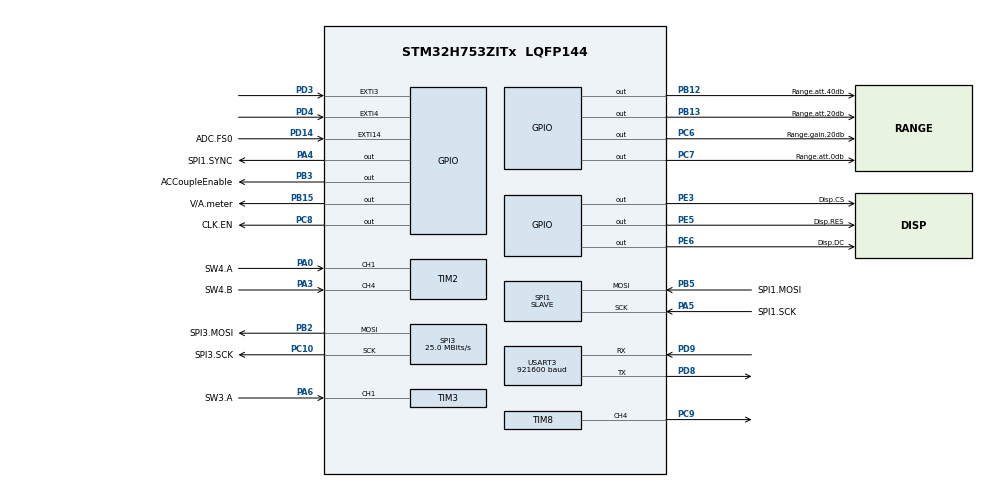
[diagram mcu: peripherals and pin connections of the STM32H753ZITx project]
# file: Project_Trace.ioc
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Dma.Request0=SPI1_RX
Dma.Request1=SPI3_TX
Dma.SPI1_RX.0.Direction=DMA_PERIPH_TO_MEMORY
Dma.SPI1_RX.0.EventEnable=DISABLE
Dma.SPI1_RX.0.FIFOMode=DMA_FIFOMODE_DISABLE
Dma.SPI1_RX.0.Instance=DMA1_Stream1
Dma.SPI1_RX.0.MemDataAlignment=DMA_MDATAALIGN_HALFWORD
Dma.SPI1_RX.0.MemInc=DMA_MINC_ENABLE
Dma.SPI1_RX.0.Mode=DMA_CIRCULAR
Dma.SPI1_RX.0.PeriphDataAlignment=DMA_PDATAALIGN_HALFWORD
Dma.SPI1_RX.0.PeriphInc=DMA_PINC_DISABLE
Dma.SPI1_RX.0.Polarity=HAL_DMAMUX_REQ_GEN_RISING
Dma.SPI1_RX.0.Priority=DMA_PRIORITY_LOW
Dma.SPI1_RX.0.RequestNumber=1
Dma.SPI1_RX.0.SignalID=NONE
Dma.SPI1_RX.0.SyncEnable=ENABLE
Dma.SPI1_RX.0.SyncPolarity=HAL_DMAMUX_SYNC_RISING
Dma.SPI1_RX.0.SyncRequestNumber=1
Dma.SPI1_RX.0.SyncSignalID=NONE
Dma.SPI3_TX.1.Direction=DMA_MEMORY_TO_PERIPH
Dma.SPI3_TX.1.EventEnable=DISABLE
Dma.SPI3_TX.1.FIFOMode=DMA_FIFOMODE_DISABLE
Dma.SPI3_TX.1.Instance=DMA1_Stream0
Dma.SPI3_TX.1.MemDataAlignment=DMA_MDATAALIGN_BYTE
Dma.SPI3_TX.1.MemInc=DMA_MINC_ENABLE
Dma.SPI3_TX.1.Mode=DMA_NORMAL
Dma.SPI3_TX.1.PeriphDataAlignment=DMA_PDATAALIGN_BYTE
Dma.SPI3_TX.1.PeriphInc=DMA_PINC_DISABLE
Dma.SPI3_TX.1.Polarity=HAL_DMAMUX_REQ_GEN_RISING
Dma.SPI3_TX.1.Priority=DMA_PRIORITY_LOW
Dma.SPI3_TX.1.RequestNumber=1
Dma.SPI3_TX.1.SignalID=NONE
Dma.SPI3_TX.1.SyncEnable=DISABLE
Dma.SPI3_TX.1.SyncPolarity=HAL_DMAMUX_SYNC_NO_EVENT
Dma.SPI3_TX.1.SyncRequestNumber=1
Dma.SPI3_TX.1.SyncSignalID=NONE
Mcu.Family=STM32H7
Mcu.Name=STM32H753ZITx
Mcu.Package=LQFP144
NVIC.DMA1_Stream0_IRQn=true\:0\:0\:false\:false\:true\:false\:true
NVIC.DMA1_Stream1_IRQn=true\:0\:0\:false\:false\:true\:false\:true
NVIC.DMAMUX1_OVR_IRQn=true\:0\:0\:false\:false\:true\:false\:true
NVIC.PriorityGroup=NVIC_PRIORITYGROUP_4
NVIC.SPI1_IRQn=true\:0\:0\:false\:false\:true\:false\:true
NVIC.SPI3_IRQn=true\:0\:0\:false\:false\:true\:false\:true
NVIC.TIM1_UP_IRQn=true\:0\:0\:true\:false\:true\:true\:true
NVIC.TIM8_UP_TIM13_IRQn=true\:0\:0\:false\:false\:true\:true\:true
PA0.GPIO_Label=SW4.A
PA0.Signal=S_TIM2_CH1_ETR
PA3.GPIO_Label=SW4.B
PA3.Signal=S_TIM2_CH4
PA4.GPIO_Label=SPI1.SYNC
PA4.GPIO_Speed=GPIO_SPEED_FREQ_HIGH
PA4.Signal=GPIO_Output
PA5.GPIO_Label=SPI1.SCK
PA5.Mode=RX_Only_Simplex_Unidirect_Slave
PA5.Signal=SPI1_SCK
PA6.GPIO_Label=SW3.A
PA6.Signal=S_TIM3_CH1
PB12.GPIO_Label=Range.att.40db
PB12.Signal=GPIO_Output
PB13.GPIO_Label=Range.att.20db
PB13.Signal=GPIO_Output
PB15.GPIO_Label=V/A.meter
PB15.Signal=GPIO_Output
PB2.GPIO_Label=SPI3.MOSI
PB2.Mode=TX_Only_Simplex_Unidirect_Master
PB2.Signal=SPI3_MOSI
PB3\ (JTDO/TRACESWO).GPIO_Label=ACCoupleEnable
PB3\ (JTDO/TRACESWO).Signal=GPIO_Output
PB5.GPIO_Label=SPI1.MOSI
PB5.Mode=RX_Only_Simplex_Unidirect_Slave
PB5.Signal=SPI1_MOSI
PC10.GPIO_Label=SPI3.SCK
PC10.Mode=TX_Only_Simplex_Unidirect_Master
PC10.Signal=SPI3_SCK
PC6.GPIO_Label=Range.gain.20db
PC6.Signal=GPIO_Output
PC7.GPIO_Label=Range.att.0db
PC7.Signal=GPIO_Output
PC8.GPIO_Label=CLK.EN
PC8.Signal=GPIO_Output
PC9.Signal=S_TIM8_CH4
PD14.GPIO_Label=ADC.FS0
PD14.GPIO_ModeDefaultEXTI=GPIO_MODE_IT_RISING
PD14.Signal=GPXTI14
PD3.Signal=GPXTI3
PD4.Signal=GPXTI4
PD8.Mode=Asynchronous
PD8.Signal=USART3_TX
PD9.Mode=Asynchronous
PD9.Signal=USART3_RX
PE3.GPIO_Label=Disp.CS
PE3.Signal=GPIO_Output
PE5.GPIO_Label=Disp.RES
PE5.Signal=GPIO_Output
PE6.GPIO_Label=Disp.DC
PE6.Signal=GPIO_Output
PH0-OSC_IN\ (PH0).Mode=HSE-External-Oscillator
PH0-OSC_IN\ (PH0).Signal=RCC_OSC_IN
PH1-OSC_OUT\ (PH1).Mode=HSE-External-Oscillator
PH1-OSC_OUT\ (PH1).Signal=RCC_OSC_OUT
ProjectManager.HeapSize=0x200
ProjectManager.StackSize=0x400
ProjectManager.TargetToolchain=STM32CubeIDE
RCC.ADCFreq_Value=129000000
RCC.APB1Freq_Value=50000000
RCC.APB2Freq_Value=100000000
RCC.APB3Freq_Value=100000000
RCC.APB4Freq_Value=100000000
RCC.CortexFreq_Value=200000000
RCC.D2PPRE1=RCC_APB1_DIV2
RCC.DIVM1=4
RCC.DIVN1=25
RCC.DIVQ1=4
RCC.HCLKFreq_Value=100000000
RCC.HPRE=RCC_HCLK_DIV2
RCC.PLLFRACN=0
RCC.SYSCLKFreq_VALUE=200000000
RCC.SYSCLKSource=RCC_SYSCLKSOURCE_PLLCLK
RCC.USBFreq_Value=100000000
SH.S_TIM2_CH1_ETR.0=TIM2_CH1,Input_Capture1_from_TI1
SH.S_TIM2_CH4.0=TIM2_CH4,Input_Capture4_from_TI4
SH.S_TIM3_CH1.0=TIM3_CH1,Input_Capture1_from_TI1
SH.S_TIM8_CH4.0=TIM8_CH4,PWM Generation4 CH4
SPI1.CLKPhase=SPI_PHASE_2EDGE
SPI1.CLKPolarity=SPI_POLARITY_LOW
SPI1.DataSize=SPI_DATASIZE_16BIT
SPI1.Direction=SPI_DIRECTION_2LINES_RXONLY
SPI1.Mode=SPI_MODE_SLAVE
SPI1.VirtualType=VM_SLAVE
SPI3.BaudRatePrescaler=SPI_BAUDRATEPRESCALER_4
SPI3.CalculateBaudRate=25.0 MBits/s
SPI3.DataSize=SPI_DATASIZE_8BIT
SPI3.Direction=SPI_DIRECTION_2LINES_TXONLY
SPI3.Mode=SPI_MODE_MASTER
SPI3.VirtualType=VM_MASTER
TIM1.Period=32768
TIM1.Prescaler=1000
TIM2.Channel-Input_Capture1_from_TI1=TIM_CHANNEL_1
TIM2.Channel-Input_Capture4_from_TI4=TIM_CHANNEL_4
TIM3.Channel-Input_Capture1_from_TI1=TIM_CHANNEL_1
TIM8.Channel-PWM\ Generation4\ CH4=TIM_CHANNEL_4
TIM8.OCFastMode_PWM-PWM\ Generation4\ CH4=TIM_OCFAST_ENABLE
TIM8.Period=3
TIM8.Prescaler=1
TIM8.Pulse-PWM\ Generation4\ CH4=2
USART3.BaudRate=921600
USART3.VirtualMode-Asynchronous=VM_ASYNC
VP_TIM1_VS_ClockSourceINT.Mode=Internal
VP_TIM8_VS_ClockSourceINT.Mode=Internal
board=custom

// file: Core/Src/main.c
/* USER CODE BEGIN Header */
/**
  ******************************************************************************
  * @file           : main.c
  * @brief          : Main program body
  ******************************************************************************
  * @attention
  *
  * Copyright (c) 2026 STMicroelectronics.
  * All rights reserved.
  *
  * This software is licensed under terms that can be found in the LICENSE file
  * in the root directory of this software component.
  * If no LICENSE file comes with this software, it is provided AS-IS.
  *
  ******************************************************************************
  */
/* USER CODE END Header */
#include "main.h"

/* USER CODE BEGIN Includes */
#include <stdio.h>
#include <stm32h7xx_hal.h>
#include <stdint.h>
#include <menu_system.h>
#include <graphics.h>

#include <adc.h>
#include <hal_oled.h>
#include <hal_signal_path.h>
#include <test_suite.h>
#include <sample_buffer.h>

#include <serialization.h>

#include <assert.h>

/* USER CODE END Includes */

/* USER CODE BEGIN PD */
//#define RUN_TESTS
/* USER CODE END PD */

SPI_HandleTypeDef hspi1;
SPI_HandleTypeDef hspi3;
DMA_HandleTypeDef hdma_spi1_rx;
DMA_HandleTypeDef hdma_spi3_tx;

TIM_HandleTypeDef htim1;
TIM_HandleTypeDef htim2;
TIM_HandleTypeDef htim3;
TIM_HandleTypeDef htim8;

UART_HandleTypeDef huart3;

void SystemClock_Config(void);
static void MX_GPIO_Init(void);
static void MX_DMA_Init(void);
static void MX_SPI3_Init(void);
static void MX_TIM2_Init(void);
static void MX_SPI1_Init(void);
static void MX_TIM3_Init(void);
static void MX_USART3_UART_Init(void);
static void MX_TIM8_Init(void);
static void MX_TIM1_Init(void);

/* USER CODE BEGIN 0 */
extern SampleBuffer sample_buffer;

int __io_putchar(int ch)
  {
   uint8_t c[1];
   c[0] = ch & 0x00FF;
   HAL_UART_Transmit(&huart3, &*c, 1, HAL_MAX_DELAY);
   return ch;
  }
/* USER CODE END 0 */

int main(void)
{

  /* MCU Configuration--------------------------------------------------------*/

  /* Reset of all peripherals, Initializes the Flash interface and the Systick. */
  HAL_Init();

  /* Configure the system clock */
  SystemClock_Config();

  /* Initialize all configured peripherals */
  MX_GPIO_Init();
  MX_DMA_Init();
  MX_SPI3_Init();
  MX_TIM2_Init();
  MX_SPI1_Init();
  MX_TIM3_Init();
  MX_USART3_UART_Init();
  MX_TIM8_Init();
  MX_TIM1_Init();
  /* USER CODE BEGIN 2 */
  //HAL_MspInit();
  //HAL_SPI_MspInit(&hspi1);

  printf("Hello, There!\r\n");
#ifdef RUN_TESTS
  printf("Running Tests!\r\n");

  //test_suite();
  while(1){}
#endif

  //__disable_irq();

  printf("Init Signal Path\n");
  hal_signal_path_init();
  hal_signal_path_attenuator_set(SignalPathAtten_0db);
  hal_signal_path_accouple_en(0);

  sample_buffer_init(&sample_buffer, 12500000); // TODO: use precise sample-rate
  printf("Init ADC\n");
  adc_init();

  printf("Init OLED\n");
  hal_oled_init();
  printf("Init Menu\n");
  menu_init();

  printf("Start ADC CLK\n");
  HAL_TIM_PWM_Start(&htim8, TIM_CHANNEL_4);

  //const char* header_labels[1] = { "x" };
  //(void)ser_file_write_csv_header(stdout, header_labels, 1);

  //__enable_irq();
  /* USER CODE END 2 */

  /* Infinite loop */
  /* USER CODE BEGIN WHILE */
  graphics_draw_rect_rel(5, 5, 10, 10);
  graphics_draw_text(8, 8, "address me");

  printf("Enter Loop\n");
  while (1)
  {
    /* USER CODE END WHILE */

    /* USER CODE BEGIN 3 */

//	  hal_oled_update_screen();
//	  for (uint32_t i = 0; i < 10000000LL; i++){}
//	  printf("Hi!\r\n");

  }
  /* USER CODE END 3 */
}

void SystemClock_Config(void)
{
  RCC_OscInitTypeDef RCC_OscInitStruct = {0};
  RCC_ClkInitTypeDef RCC_ClkInitStruct = {0};

  /** Supply configuration update enable
  */
  HAL_PWREx_ConfigSupply(PWR_LDO_SUPPLY);
  /** Configure the main internal regulator output voltage
  */
  __HAL_PWR_VOLTAGESCALING_CONFIG(PWR_REGULATOR_VOLTAGE_SCALE3);

  while(!__HAL_PWR_GET_FLAG(PWR_FLAG_VOSRDY)) {}
  /** Initializes the RCC Oscillators according to the specified parameters
  * in the RCC_OscInitTypeDef structure.
  */
  RCC_OscInitStruct.OscillatorType = RCC_OSCILLATORTYPE_HSI;
  RCC_OscInitStruct.HSIState = RCC_HSI_DIV1;
  RCC_OscInitStruct.HSICalibrationValue = RCC_HSICALIBRATION_DEFAULT;
  RCC_OscInitStruct.PLL.PLLState = RCC_PLL_ON;
  RCC_OscInitStruct.PLL.PLLSource = RCC_PLLSOURCE_HSI;
  RCC_OscInitStruct.PLL.PLLM = 4;
  RCC_OscInitStruct.PLL.PLLN = 25;
  RCC_OscInitStruct.PLL.PLLP = 2;
  RCC_OscInitStruct.PLL.PLLQ = 4;
  RCC_OscInitStruct.PLL.PLLR = 2;
  RCC_OscInitStruct.PLL.PLLRGE = RCC_PLL1VCIRANGE_3;
  RCC_OscInitStruct.PLL.PLLVCOSEL = RCC_PLL1VCOWIDE;
  RCC_OscInitStruct.PLL.PLLFRACN = 0;
  if (HAL_RCC_OscConfig(&RCC_OscInitStruct) != HAL_OK)
  {
    Error_Handler();
  }
  /** Initializes the CPU, AHB and APB buses clocks
  */
  RCC_ClkInitStruct.ClockType = RCC_CLOCKTYPE_HCLK|RCC_CLOCKTYPE_SYSCLK
                              |RCC_CLOCKTYPE_PCLK1|RCC_CLOCKTYPE_PCLK2
                              |RCC_CLOCKTYPE_D3PCLK1|RCC_CLOCKTYPE_D1PCLK1;
  RCC_ClkInitStruct.SYSCLKSource = RCC_SYSCLKSOURCE_PLLCLK;
  RCC_ClkInitStruct.SYSCLKDivider = RCC_SYSCLK_DIV1;
  RCC_ClkInitStruct.AHBCLKDivider = RCC_HCLK_DIV2;
  RCC_ClkInitStruct.APB3CLKDivider = RCC_APB3_DIV1;
  RCC_ClkInitStruct.APB1CLKDivider = RCC_APB1_DIV2;
  RCC_ClkInitStruct.APB2CLKDivider = RCC_APB2_DIV1;
  RCC_ClkInitStruct.APB4CLKDivider = RCC_APB4_DIV1;

  if (HAL_RCC_ClockConfig(&RCC_ClkInitStruct, FLASH_LATENCY_2) != HAL_OK)
  {
    Error_Handler();
  }
}

static void MX_SPI1_Init(void)
{

  /* SPI1 parameter configuration*/
  hspi1.Instance = SPI1;
  hspi1.Init.Mode = SPI_MODE_SLAVE;
  hspi1.Init.Direction = SPI_DIRECTION_2LINES_RXONLY;
  hspi1.Init.DataSize = SPI_DATASIZE_16BIT;
  hspi1.Init.CLKPolarity = SPI_POLARITY_LOW;
  hspi1.Init.CLKPhase = SPI_PHASE_2EDGE;
  hspi1.Init.NSS = SPI_NSS_SOFT;
  hspi1.Init.FirstBit = SPI_FIRSTBIT_MSB;
  hspi1.Init.TIMode = SPI_TIMODE_DISABLE;
  hspi1.Init.CRCCalculation = SPI_CRCCALCULATION_DISABLE;
  hspi1.Init.CRCPolynomial = 0x0;
  hspi1.Init.NSSPMode = SPI_NSS_PULSE_DISABLE;
  hspi1.Init.NSSPolarity = SPI_NSS_POLARITY_LOW;
  hspi1.Init.FifoThreshold = SPI_FIFO_THRESHOLD_01DATA;
  hspi1.Init.TxCRCInitializationPattern = SPI_CRC_INITIALIZATION_ALL_ZERO_PATTERN;
  hspi1.Init.RxCRCInitializationPattern = SPI_CRC_INITIALIZATION_ALL_ZERO_PATTERN;
  hspi1.Init.MasterSSIdleness = SPI_MASTER_SS_IDLENESS_00CYCLE;
  hspi1.Init.MasterInterDataIdleness = SPI_MASTER_INTERDATA_IDLENESS_00CYCLE;
  hspi1.Init.MasterReceiverAutoSusp = SPI_MASTER_RX_AUTOSUSP_DISABLE;
  hspi1.Init.MasterKeepIOState = SPI_MASTER_KEEP_IO_STATE_DISABLE;
  hspi1.Init.IOSwap = SPI_IO_SWAP_DISABLE;
  if (HAL_SPI_Init(&hspi1) != HAL_OK)
  {
    Error_Handler();
  }

}

static void MX_SPI3_Init(void)
{

  /* SPI3 parameter configuration*/
  hspi3.Instance = SPI3;
  hspi3.Init.Mode = SPI_MODE_MASTER;
  hspi3.Init.Direction = SPI_DIRECTION_2LINES_TXONLY;
  hspi3.Init.DataSize = SPI_DATASIZE_8BIT;
  hspi3.Init.CLKPolarity = SPI_POLARITY_LOW;
  hspi3.Init.CLKPhase = SPI_PHASE_1EDGE;
  hspi3.Init.NSS = SPI_NSS_SOFT;
  hspi3.Init.BaudRatePrescaler = SPI_BAUDRATEPRESCALER_4;
  hspi3.Init.FirstBit = SPI_FIRSTBIT_MSB;
  hspi3.Init.TIMode = SPI_TIMODE_DISABLE;
  hspi3.Init.CRCCalculation = SPI_CRCCALCULATION_DISABLE;
  hspi3.Init.CRCPolynomial = 0x0;
  hspi3.Init.NSSPMode = SPI_NSS_PULSE_ENABLE;
  hspi3.Init.NSSPolarity = SPI_NSS_POLARITY_LOW;
  hspi3.Init.FifoThreshold = SPI_FIFO_THRESHOLD_01DATA;
  hspi3.Init.TxCRCInitializationPattern = SPI_CRC_INITIALIZATION_ALL_ZERO_PATTERN;
  hspi3.Init.RxCRCInitializationPattern = SPI_CRC_INITIALIZATION_ALL_ZERO_PATTERN;
  hspi3.Init.MasterSSIdleness = SPI_MASTER_SS_IDLENESS_00CYCLE;
  hspi3.Init.MasterInterDataIdleness = SPI_MASTER_INTERDATA_IDLENESS_00CYCLE;
  hspi3.Init.MasterReceiverAutoSusp = SPI_MASTER_RX_AUTOSUSP_DISABLE;
  hspi3.Init.MasterKeepIOState = SPI_MASTER_KEEP_IO_STATE_DISABLE;
  hspi3.Init.IOSwap = SPI_IO_SWAP_DISABLE;
  if (HAL_SPI_Init(&hspi3) != HAL_OK)
  {
    Error_Handler();
  }

}

static void MX_TIM1_Init(void)
{

  TIM_ClockConfigTypeDef sClockSourceConfig = {0};
  TIM_MasterConfigTypeDef sMasterConfig = {0};

  htim1.Instance = TIM1;
  htim1.Init.Prescaler = 1000;
  htim1.Init.CounterMode = TIM_COUNTERMODE_UP;
  htim1.Init.Period = 32768;
  htim1.Init.ClockDivision = TIM_CLOCKDIVISION_DIV1;
  htim1.Init.RepetitionCounter = 0;
  htim1.Init.AutoReloadPreload = TIM_AUTORELOAD_PRELOAD_DISABLE;
  if (HAL_TIM_Base_Init(&htim1) != HAL_OK)
  {
    Error_Handler();
  }
  sClockSourceConfig.ClockSource = TIM_CLOCKSOURCE_INTERNAL;
  if (HAL_TIM_ConfigClockSource(&htim1, &sClockSourceConfig) != HAL_OK)
  {
    Error_Handler();
  }
  sMasterConfig.MasterOutputTrigger = TIM_TRGO_RESET;
  sMasterConfig.MasterOutputTrigger2 = TIM_TRGO2_RESET;
  sMasterConfig.MasterSlaveMode = TIM_MASTERSLAVEMODE_DISABLE;
  if (HAL_TIMEx_MasterConfigSynchronization(&htim1, &sMasterConfig) != HAL_OK)
  {
    Error_Handler();
  }

}

static void MX_TIM2_Init(void)
{

  TIM_MasterConfigTypeDef sMasterConfig = {0};
  TIM_IC_InitTypeDef sConfigIC = {0};

  htim2.Instance = TIM2;
  htim2.Init.Prescaler = 0;
  htim2.Init.CounterMode = TIM_COUNTERMODE_UP;
  htim2.Init.Period = 4294967295;
  htim2.Init.ClockDivision = TIM_CLOCKDIVISION_DIV1;
  htim2.Init.AutoReloadPreload = TIM_AUTORELOAD_PRELOAD_DISABLE;
  if (HAL_TIM_IC_Init(&htim2) != HAL_OK)
  {
    Error_Handler();
  }
  sMasterConfig.MasterOutputTrigger = TIM_TRGO_RESET;
  sMasterConfig.MasterSlaveMode = TIM_MASTERSLAVEMODE_DISABLE;
  if (HAL_TIMEx_MasterConfigSynchronization(&htim2, &sMasterConfig) != HAL_OK)
  {
    Error_Handler();
  }
  sConfigIC.ICPolarity = TIM_INPUTCHANNELPOLARITY_RISING;
  sConfigIC.ICSelection = TIM_ICSELECTION_DIRECTTI;
  sConfigIC.ICPrescaler = TIM_ICPSC_DIV1;
  sConfigIC.ICFilter = 0;
  if (HAL_TIM_IC_ConfigChannel(&htim2, &sConfigIC, TIM_CHANNEL_1) != HAL_OK)
  {
    Error_Handler();
  }
  if (HAL_TIM_IC_ConfigChannel(&htim2, &sConfigIC, TIM_CHANNEL_4) != HAL_OK)
  {
    Error_Handler();
  }

}

static void MX_TIM3_Init(void)
{

  TIM_MasterConfigTypeDef sMasterConfig = {0};
  TIM_IC_InitTypeDef sConfigIC = {0};

  htim3.Instance = TIM3;
  htim3.Init.Prescaler = 0;
  htim3.Init.CounterMode = TIM_COUNTERMODE_UP;
  htim3.Init.Period = 65535;
  htim3.Init.ClockDivision = TIM_CLOCKDIVISION_DIV1;
  htim3.Init.AutoReloadPreload = TIM_AUTORELOAD_PRELOAD_DISABLE;
  if (HAL_TIM_IC_Init(&htim3) != HAL_OK)
  {
    Error_Handler();
  }
  sMasterConfig.MasterOutputTrigger = TIM_TRGO_RESET;
  sMasterConfig.MasterSlaveMode = TIM_MASTERSLAVEMODE_DISABLE;
  if (HAL_TIMEx_MasterConfigSynchronization(&htim3, &sMasterConfig) != HAL_OK)
  {
    Error_Handler();
  }
  sConfigIC.ICPolarity = TIM_INPUTCHANNELPOLARITY_RISING;
  sConfigIC.ICSelection = TIM_ICSELECTION_DIRECTTI;
  sConfigIC.ICPrescaler = TIM_ICPSC_DIV1;
  sConfigIC.ICFilter = 0;
  if (HAL_TIM_IC_ConfigChannel(&htim3, &sConfigIC, TIM_CHANNEL_1) != HAL_OK)
  {
    Error_Handler();
  }

}

static void MX_TIM8_Init(void)
{

  TIM_ClockConfigTypeDef sClockSourceConfig = {0};
  TIM_MasterConfigTypeDef sMasterConfig = {0};
  TIM_OC_InitTypeDef sConfigOC = {0};
  TIM_BreakDeadTimeConfigTypeDef sBreakDeadTimeConfig = {0};

  htim8.Instance = TIM8;
  htim8.Init.Prescaler = 1;
  htim8.Init.CounterMode = TIM_COUNTERMODE_UP;
  htim8.Init.Period = 3;
  htim8.Init.ClockDivision = TIM_CLOCKDIVISION_DIV1;
  htim8.Init.RepetitionCounter = 0;
  htim8.Init.AutoReloadPreload = TIM_AUTORELOAD_PRELOAD_DISABLE;
  if (HAL_TIM_Base_Init(&htim8) != HAL_OK)
  {
    Error_Handler();
  }
  sClockSourceConfig.ClockSource = TIM_CLOCKSOURCE_INTERNAL;
  if (HAL_TIM_ConfigClockSource(&htim8, &sClockSourceConfig) != HAL_OK)
  {
    Error_Handler();
  }
  if (HAL_TIM_PWM_Init(&htim8) != HAL_OK)
  {
    Error_Handler();
  }
  sMasterConfig.MasterOutputTrigger = TIM_TRGO_RESET;
  sMasterConfig.MasterOutputTrigger2 = TIM_TRGO2_RESET;
  sMasterConfig.MasterSlaveMode = TIM_MASTERSLAVEMODE_DISABLE;
  if (HAL_TIMEx_MasterConfigSynchronization(&htim8, &sMasterConfig) != HAL_OK)
  {
    Error_Handler();
  }
  sConfigOC.OCMode = TIM_OCMODE_PWM1;
  sConfigOC.Pulse = 2;
  sConfigOC.OCPolarity = TIM_OCPOLARITY_HIGH;
  sConfigOC.OCFastMode = TIM_OCFAST_ENABLE;
  sConfigOC.OCIdleState = TIM_OCIDLESTATE_RESET;
  sConfigOC.OCNIdleState = TIM_OCNIDLESTATE_RESET;
  if (HAL_TIM_PWM_ConfigChannel(&htim8, &sConfigOC, TIM_CHANNEL_4) != HAL_OK)
  {
    Error_Handler();
  }
  sBreakDeadTimeConfig.OffStateRunMode = TIM_OSSR_DISABLE;
  sBreakDeadTimeConfig.OffStateIDLEMode = TIM_OSSI_DISABLE;
  sBreakDeadTimeConfig.LockLevel = TIM_LOCKLEVEL_OFF;
  sBreakDeadTimeConfig.DeadTime = 0;
  sBreakDeadTimeConfig.BreakState = TIM_BREAK_DISABLE;
  sBreakDeadTimeConfig.BreakPolarity = TIM_BREAKPOLARITY_HIGH;
  sBreakDeadTimeConfig.BreakFilter = 0;
  sBreakDeadTimeConfig.Break2State = TIM_BREAK2_DISABLE;
  sBreakDeadTimeConfig.Break2Polarity = TIM_BREAK2POLARITY_HIGH;
  sBreakDeadTimeConfig.Break2Filter = 0;
  sBreakDeadTimeConfig.AutomaticOutput = TIM_AUTOMATICOUTPUT_DISABLE;
  if (HAL_TIMEx_ConfigBreakDeadTime(&htim8, &sBreakDeadTimeConfig) != HAL_OK)
  {
    Error_Handler();
  }
  HAL_TIM_MspPostInit(&htim8);

}

static void MX_USART3_UART_Init(void)
{

  huart3.Instance = USART3;
  huart3.Init.BaudRate = 921600;
  huart3.Init.WordLength = UART_WORDLENGTH_8B;
  huart3.Init.StopBits = UART_STOPBITS_1;
  huart3.Init.Parity = UART_PARITY_NONE;
  huart3.Init.Mode = UART_MODE_TX_RX;
  huart3.Init.HwFlowCtl = UART_HWCONTROL_NONE;
  huart3.Init.OverSampling = UART_OVERSAMPLING_16;
  huart3.Init.OneBitSampling = UART_ONE_BIT_SAMPLE_DISABLE;
  huart3.Init.ClockPrescaler = UART_PRESCALER_DIV1;
  huart3.AdvancedInit.AdvFeatureInit = UART_ADVFEATURE_NO_INIT;
  if (HAL_UART_Init(&huart3) != HAL_OK)
  {
    Error_Handler();
  }
  if (HAL_UARTEx_SetTxFifoThreshold(&huart3, UART_TXFIFO_THRESHOLD_1_8) != HAL_OK)
  {
    Error_Handler();
  }
  if (HAL_UARTEx_SetRxFifoThreshold(&huart3, UART_RXFIFO_THRESHOLD_1_8) != HAL_OK)
  {
    Error_Handler();
  }
  if (HAL_UARTEx_DisableFifoMode(&huart3) != HAL_OK)
  {
    Error_Handler();
  }

}

static void MX_DMA_Init(void)
{

  /* DMA controller clock enable */
  __HAL_RCC_DMA1_CLK_ENABLE();

  /* DMA interrupt init */
  /* DMA1_Stream0_IRQn interrupt configuration */
  HAL_NVIC_SetPriority(DMA1_Stream0_IRQn, 0, 0);
  HAL_NVIC_EnableIRQ(DMA1_Stream0_IRQn);
  /* DMA1_Stream1_IRQn interrupt configuration */
  HAL_NVIC_SetPriority(DMA1_Stream1_IRQn, 0, 0);
  HAL_NVIC_EnableIRQ(DMA1_Stream1_IRQn);
  /* DMAMUX1_OVR_IRQn interrupt configuration */
  HAL_NVIC_SetPriority(DMAMUX1_OVR_IRQn, 0, 0);
  HAL_NVIC_EnableIRQ(DMAMUX1_OVR_IRQn);

}

static void MX_GPIO_Init(void)
{
  GPIO_InitTypeDef GPIO_InitStruct = {0};

  /* GPIO Ports Clock Enable */
  __HAL_RCC_GPIOE_CLK_ENABLE();
  __HAL_RCC_GPIOH_CLK_ENABLE();
  __HAL_RCC_GPIOA_CLK_ENABLE();
  __HAL_RCC_GPIOB_CLK_ENABLE();
  __HAL_RCC_GPIOD_CLK_ENABLE();
  __HAL_RCC_GPIOC_CLK_ENABLE();

  /*Configure GPIO pin Output Level */
  HAL_GPIO_WritePin(GPIOE, Disp_CS_Pin|Disp_RES_Pin|Disp_DC_Pin, GPIO_PIN_RESET);

  /*Configure GPIO pin Output Level */
  HAL_GPIO_WritePin(SPI1_SYNC_GPIO_Port, SPI1_SYNC_Pin, GPIO_PIN_RESET);

  /*Configure GPIO pin Output Level */
  HAL_GPIO_WritePin(GPIOB, Range_att_40db_Pin|Range_att_20db_Pin|V_A_meter_Pin|ACCoupleEnable_Pin, GPIO_PIN_RESET);

  /*Configure GPIO pin Output Level */
  HAL_GPIO_WritePin(GPIOC, Range_gain_20db_Pin|Range_att_0db_Pin|CLK_EN_Pin, GPIO_PIN_RESET);

  /*Configure GPIO pins : Disp_CS_Pin Disp_RES_Pin Disp_DC_Pin */
  GPIO_InitStruct.Pin = Disp_CS_Pin|Disp_RES_Pin|Disp_DC_Pin;
  GPIO_InitStruct.Mode = GPIO_MODE_OUTPUT_PP;
  GPIO_InitStruct.Pull = GPIO_NOPULL;
  GPIO_InitStruct.Speed = GPIO_SPEED_FREQ_LOW;
  HAL_GPIO_Init(GPIOE, &GPIO_InitStruct);

  /*Configure GPIO pin : SPI1_SYNC_Pin */
  GPIO_InitStruct.Pin = SPI1_SYNC_Pin;
  GPIO_InitStruct.Mode = GPIO_MODE_OUTPUT_PP;
  GPIO_InitStruct.Pull = GPIO_NOPULL;
  GPIO_InitStruct.Speed = GPIO_SPEED_FREQ_HIGH;
  HAL_GPIO_Init(SPI1_SYNC_GPIO_Port, &GPIO_InitStruct);

  /*Configure GPIO pins : Range_att_40db_Pin Range_att_20db_Pin V_A_meter_Pin ACCoupleEnable_Pin */
  GPIO_InitStruct.Pin = Range_att_40db_Pin|Range_att_20db_Pin|V_A_meter_Pin|ACCoupleEnable_Pin;
  GPIO_InitStruct.Mode = GPIO_MODE_OUTPUT_PP;
  GPIO_InitStruct.Pull = GPIO_NOPULL;
  GPIO_InitStruct.Speed = GPIO_SPEED_FREQ_LOW;
  HAL_GPIO_Init(GPIOB, &GPIO_InitStruct);

  /*Configure GPIO pin : ADC_FS0_Pin */
  GPIO_InitStruct.Pin = ADC_FS0_Pin;
  GPIO_InitStruct.Mode = GPIO_MODE_IT_RISING;
  GPIO_InitStruct.Pull = GPIO_NOPULL;
  HAL_GPIO_Init(ADC_FS0_GPIO_Port, &GPIO_InitStruct);

  /*Configure GPIO pins : Range_gain_20db_Pin Range_att_0db_Pin CLK_EN_Pin */
  GPIO_InitStruct.Pin = Range_gain_20db_Pin|Range_att_0db_Pin|CLK_EN_Pin;
  GPIO_InitStruct.Mode = GPIO_MODE_OUTPUT_PP;
  GPIO_InitStruct.Pull = GPIO_NOPULL;
  GPIO_InitStruct.Speed = GPIO_SPEED_FREQ_LOW;
  HAL_GPIO_Init(GPIOC, &GPIO_InitStruct);

  /*Configure GPIO pins : SW2_Pin SW1_Pin */
  GPIO_InitStruct.Pin = SW2_Pin|SW1_Pin;
  GPIO_InitStruct.Mode = GPIO_MODE_INPUT;
  GPIO_InitStruct.Pull = GPIO_NOPULL;
  HAL_GPIO_Init(GPIOD, &GPIO_InitStruct);

}

/* USER CODE BEGIN 4 */
void HAL_SPI_RxCpltCallback(SPI_HandleTypeDef *hspi)
{
	//printf("HAL_SPI_RxCpltCallback\n");

    if (hspi->Instance == SPI1){
        __disable_irq();
    	adc_dma_done();
    	__enable_irq();
    }
    else if (hspi->Instance == SPI3){
    	// TODO add display SPI3
    }
}

void HAL_SPI_RxErrorCallback(SPI_HandleTypeDef *hspi) {
	printf("HAL_SPI_RxErrorCallback\n");
	(void) hspi;
}

/* USER CODE END 4 */

void Error_Handler(void)
{
  __disable_irq();
  while (1)
  {
  }
}
